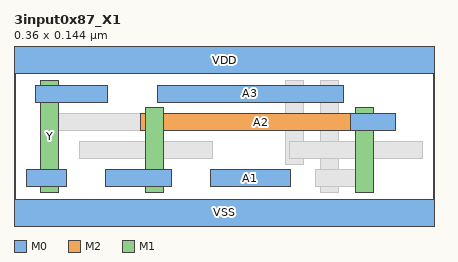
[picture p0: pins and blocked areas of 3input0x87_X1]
MACRO 3input0x87_X1
  CLASS CORE ;
  ORIGIN 0 0 ;
  FOREIGN 3input0x87_X1 0 0 ;
  SIZE 0.3600 BY 0.1440 ;
  SYMMETRY X Y ;
  SITE coresite ;
  PIN A1
    DIRECTION INPUT ;
    USE SIGNAL ;
    PORT
      LAYER M0 ;
        RECT 0.1680 0.0290 0.2370 0.0430 ;
    END
  END A1
  PIN A2
    DIRECTION INPUT ;
    USE SIGNAL ;
    PORT
      LAYER M2 ;
        RECT 0.1080 0.0770 0.3150 0.0910 ;
      LAYER M1 ;
        RECT 0.1130 0.0240 0.1280 0.0960 ;
        RECT 0.2930 0.0240 0.3080 0.0960 ;
      LAYER M0 ;
        RECT 0.2880 0.0770 0.3270 0.0910 ;
        RECT 0.0780 0.0290 0.1350 0.0430 ;
    END
  END A2
  PIN A3
    DIRECTION INPUT ;
    USE SIGNAL ;
    PORT
      LAYER M0 ;
        RECT 0.1230 0.1010 0.2820 0.1150 ;
    END
  END A3
  PIN Y
    DIRECTION OUTPUT ;
    USE SIGNAL ;
    PORT
      LAYER M1 ;
        RECT 0.0230 0.0240 0.0380 0.1200 ;
      LAYER M0 ;
        RECT 0.0180 0.1010 0.0800 0.1150 ;
        RECT 0.0110 0.0290 0.0450 0.0430 ;
    END
  END Y
  PIN VDD
    DIRECTION INOUT ;
    USE POWER ;
    SHAPE ABUTMENT ;
    PORT
      LAYER M0 ;
        RECT 0.0000 0.1260 0.3600 0.1620 ;
    END
  END VDD
  PIN VSS
    DIRECTION INOUT ;
    USE GROUND ;
    SHAPE ABUTMENT ;
    PORT
      LAYER M0 ;
        RECT 0.0000 -0.0180 0.3600 0.0180 ;
    END
  END VSS
  OBS
    LAYER M2 ;
      RECT 0.2250 0.1010 0.2820 0.1150 ;
    LAYER V1 ;
      RECT 0.2330 0.1010 0.2470 0.1150 ;
      RECT 0.2630 0.1010 0.2770 0.1150 ;
      RECT 0.1130 0.0770 0.1270 0.0910 ;
      RECT 0.2930 0.0770 0.3070 0.0910 ;
    LAYER M1 ;
      RECT 0.2330 0.0480 0.2480 0.1200 ;
      RECT 0.2630 0.0240 0.2780 0.1200 ;
    LAYER V0 ;
      RECT 0.0230 0.1010 0.0370 0.1150 ;
      RECT 0.0230 0.0290 0.0370 0.0430 ;
      RECT 0.2330 0.0770 0.2470 0.0910 ;
      RECT 0.2630 0.0290 0.2770 0.0430 ;
      RECT 0.1130 0.0290 0.1270 0.0430 ;
      RECT 0.2930 0.0770 0.3070 0.0910 ;
    LAYER M0 ;
      RECT 0.2580 0.0290 0.3050 0.0430 ;
      RECT 0.0560 0.0530 0.1700 0.0670 ;
      RECT 0.2360 0.0530 0.3500 0.0670 ;
      RECT 0.0330 0.0770 0.2600 0.0910 ;
  END
END 3input0x87_X1
